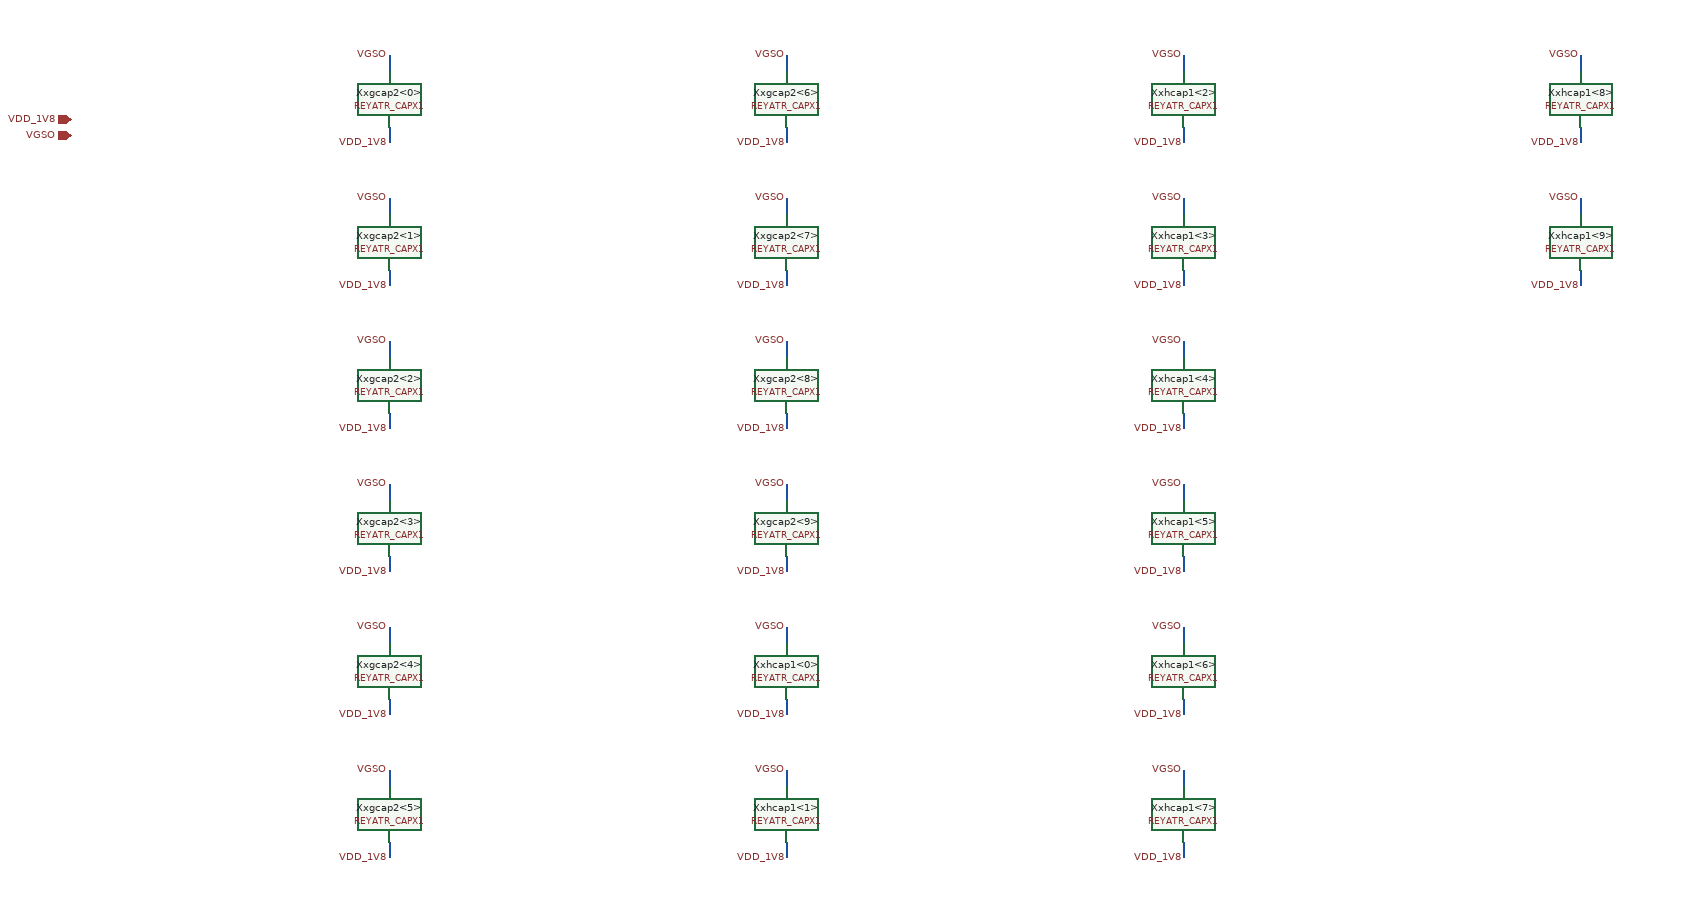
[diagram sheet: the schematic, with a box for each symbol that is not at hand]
v {xschem version=3.0.0 file_version=1.2 }
G {}
K {}
V {}
S {}
E {}
C {devices/iopin.sym} 0 0 0 0 {name=p0 lab=VDD_1V8}
C {devices/iopin.sym} 0 20 0 0 {name=p1 lab=VGSO}
C {REY_ATR_SKY130A/REYATR_CAPX1.sym} 400 0 0 0 {name=Xxgcap2<0>}
N 400.0 -80.0 400.0 -60.0 {lab=VGSO}
C {devices/lab_pin.sym} 400.0 -80.0 3 0 {name=l0 sig_type=std_logic lab=VGSO }
N 400.0 30.0 400.0 10.0 {lab=VDD_1V8}
C {devices/lab_pin.sym} 400.0 30.0 1 0 {name=l1 sig_type=std_logic lab=VDD_1V8 }
C {REY_ATR_SKY130A/REYATR_CAPX1.sym} 400 180.0 0 0 {name=Xxgcap2<1>}
N 400.0 100.0 400.0 120.0 {lab=VGSO}
C {devices/lab_pin.sym} 400.0 100.0 3 0 {name=l2 sig_type=std_logic lab=VGSO }
N 400.0 210.0 400.0 190.0 {lab=VDD_1V8}
C {devices/lab_pin.sym} 400.0 210.0 1 0 {name=l3 sig_type=std_logic lab=VDD_1V8 }
C {REY_ATR_SKY130A/REYATR_CAPX1.sym} 400 360.0 0 0 {name=Xxgcap2<2>}
N 400.0 280.0 400.0 300.0 {lab=VGSO}
C {devices/lab_pin.sym} 400.0 280.0 3 0 {name=l4 sig_type=std_logic lab=VGSO }
N 400.0 390.0 400.0 370.0 {lab=VDD_1V8}
C {devices/lab_pin.sym} 400.0 390.0 1 0 {name=l5 sig_type=std_logic lab=VDD_1V8 }
C {REY_ATR_SKY130A/REYATR_CAPX1.sym} 400 540.0 0 0 {name=Xxgcap2<3>}
N 400.0 460.0 400.0 480.0 {lab=VGSO}
C {devices/lab_pin.sym} 400.0 460.0 3 0 {name=l6 sig_type=std_logic lab=VGSO }
N 400.0 570.0 400.0 550.0 {lab=VDD_1V8}
C {devices/lab_pin.sym} 400.0 570.0 1 0 {name=l7 sig_type=std_logic lab=VDD_1V8 }
C {REY_ATR_SKY130A/REYATR_CAPX1.sym} 400 720.0 0 0 {name=Xxgcap2<4>}
N 400.0 640.0 400.0 660.0 {lab=VGSO}
C {devices/lab_pin.sym} 400.0 640.0 3 0 {name=l8 sig_type=std_logic lab=VGSO }
N 400.0 750.0 400.0 730.0 {lab=VDD_1V8}
C {devices/lab_pin.sym} 400.0 750.0 1 0 {name=l9 sig_type=std_logic lab=VDD_1V8 }
C {REY_ATR_SKY130A/REYATR_CAPX1.sym} 400 900.0 0 0 {name=Xxgcap2<5>}
N 400.0 820.0 400.0 840.0 {lab=VGSO}
C {devices/lab_pin.sym} 400.0 820.0 3 0 {name=l10 sig_type=std_logic lab=VGSO }
N 400.0 930.0 400.0 910.0 {lab=VDD_1V8}
C {devices/lab_pin.sym} 400.0 930.0 1 0 {name=l11 sig_type=std_logic lab=VDD_1V8 }
C {REY_ATR_SKY130A/REYATR_CAPX1.sym} 900 0 0 0 {name=Xxgcap2<6>}
N 900.0 -80.0 900.0 -60.0 {lab=VGSO}
C {devices/lab_pin.sym} 900.0 -80.0 3 0 {name=l12 sig_type=std_logic lab=VGSO }
N 900.0 30.0 900.0 10.0 {lab=VDD_1V8}
C {devices/lab_pin.sym} 900.0 30.0 1 0 {name=l13 sig_type=std_logic lab=VDD_1V8 }
C {REY_ATR_SKY130A/REYATR_CAPX1.sym} 900 180.0 0 0 {name=Xxgcap2<7>}
N 900.0 100.0 900.0 120.0 {lab=VGSO}
C {devices/lab_pin.sym} 900.0 100.0 3 0 {name=l14 sig_type=std_logic lab=VGSO }
N 900.0 210.0 900.0 190.0 {lab=VDD_1V8}
C {devices/lab_pin.sym} 900.0 210.0 1 0 {name=l15 sig_type=std_logic lab=VDD_1V8 }
C {REY_ATR_SKY130A/REYATR_CAPX1.sym} 900 360.0 0 0 {name=Xxgcap2<8>}
N 900.0 280.0 900.0 300.0 {lab=VGSO}
C {devices/lab_pin.sym} 900.0 280.0 3 0 {name=l16 sig_type=std_logic lab=VGSO }
N 900.0 390.0 900.0 370.0 {lab=VDD_1V8}
C {devices/lab_pin.sym} 900.0 390.0 1 0 {name=l17 sig_type=std_logic lab=VDD_1V8 }
C {REY_ATR_SKY130A/REYATR_CAPX1.sym} 900 540.0 0 0 {name=Xxgcap2<9>}
N 900.0 460.0 900.0 480.0 {lab=VGSO}
C {devices/lab_pin.sym} 900.0 460.0 3 0 {name=l18 sig_type=std_logic lab=VGSO }
N 900.0 570.0 900.0 550.0 {lab=VDD_1V8}
C {devices/lab_pin.sym} 900.0 570.0 1 0 {name=l19 sig_type=std_logic lab=VDD_1V8 }
C {REY_ATR_SKY130A/REYATR_CAPX1.sym} 900 720.0 0 0 {name=Xxhcap1<0>}
N 900.0 640.0 900.0 660.0 {lab=VGSO}
C {devices/lab_pin.sym} 900.0 640.0 3 0 {name=l20 sig_type=std_logic lab=VGSO }
N 900.0 750.0 900.0 730.0 {lab=VDD_1V8}
C {devices/lab_pin.sym} 900.0 750.0 1 0 {name=l21 sig_type=std_logic lab=VDD_1V8 }
C {REY_ATR_SKY130A/REYATR_CAPX1.sym} 900 900.0 0 0 {name=Xxhcap1<1>}
N 900.0 820.0 900.0 840.0 {lab=VGSO}
C {devices/lab_pin.sym} 900.0 820.0 3 0 {name=l22 sig_type=std_logic lab=VGSO }
N 900.0 930.0 900.0 910.0 {lab=VDD_1V8}
C {devices/lab_pin.sym} 900.0 930.0 1 0 {name=l23 sig_type=std_logic lab=VDD_1V8 }
C {REY_ATR_SKY130A/REYATR_CAPX1.sym} 1400 0 0 0 {name=Xxhcap1<2>}
N 1400.0 -80.0 1400.0 -60.0 {lab=VGSO}
C {devices/lab_pin.sym} 1400.0 -80.0 3 0 {name=l24 sig_type=std_logic lab=VGSO }
N 1400.0 30.0 1400.0 10.0 {lab=VDD_1V8}
C {devices/lab_pin.sym} 1400.0 30.0 1 0 {name=l25 sig_type=std_logic lab=VDD_1V8 }
C {REY_ATR_SKY130A/REYATR_CAPX1.sym} 1400 180.0 0 0 {name=Xxhcap1<3>}
N 1400.0 100.0 1400.0 120.0 {lab=VGSO}
C {devices/lab_pin.sym} 1400.0 100.0 3 0 {name=l26 sig_type=std_logic lab=VGSO }
N 1400.0 210.0 1400.0 190.0 {lab=VDD_1V8}
C {devices/lab_pin.sym} 1400.0 210.0 1 0 {name=l27 sig_type=std_logic lab=VDD_1V8 }
C {REY_ATR_SKY130A/REYATR_CAPX1.sym} 1400 360.0 0 0 {name=Xxhcap1<4>}
N 1400.0 280.0 1400.0 300.0 {lab=VGSO}
C {devices/lab_pin.sym} 1400.0 280.0 3 0 {name=l28 sig_type=std_logic lab=VGSO }
N 1400.0 390.0 1400.0 370.0 {lab=VDD_1V8}
C {devices/lab_pin.sym} 1400.0 390.0 1 0 {name=l29 sig_type=std_logic lab=VDD_1V8 }
C {REY_ATR_SKY130A/REYATR_CAPX1.sym} 1400 540.0 0 0 {name=Xxhcap1<5>}
N 1400.0 460.0 1400.0 480.0 {lab=VGSO}
C {devices/lab_pin.sym} 1400.0 460.0 3 0 {name=l30 sig_type=std_logic lab=VGSO }
N 1400.0 570.0 1400.0 550.0 {lab=VDD_1V8}
C {devices/lab_pin.sym} 1400.0 570.0 1 0 {name=l31 sig_type=std_logic lab=VDD_1V8 }
C {REY_ATR_SKY130A/REYATR_CAPX1.sym} 1400 720.0 0 0 {name=Xxhcap1<6>}
N 1400.0 640.0 1400.0 660.0 {lab=VGSO}
C {devices/lab_pin.sym} 1400.0 640.0 3 0 {name=l32 sig_type=std_logic lab=VGSO }
N 1400.0 750.0 1400.0 730.0 {lab=VDD_1V8}
C {devices/lab_pin.sym} 1400.0 750.0 1 0 {name=l33 sig_type=std_logic lab=VDD_1V8 }
C {REY_ATR_SKY130A/REYATR_CAPX1.sym} 1400 900.0 0 0 {name=Xxhcap1<7>}
N 1400.0 820.0 1400.0 840.0 {lab=VGSO}
C {devices/lab_pin.sym} 1400.0 820.0 3 0 {name=l34 sig_type=std_logic lab=VGSO }
N 1400.0 930.0 1400.0 910.0 {lab=VDD_1V8}
C {devices/lab_pin.sym} 1400.0 930.0 1 0 {name=l35 sig_type=std_logic lab=VDD_1V8 }
C {REY_ATR_SKY130A/REYATR_CAPX1.sym} 1900 0 0 0 {name=Xxhcap1<8>}
N 1900.0 -80.0 1900.0 -60.0 {lab=VGSO}
C {devices/lab_pin.sym} 1900.0 -80.0 3 0 {name=l36 sig_type=std_logic lab=VGSO }
N 1900.0 30.0 1900.0 10.0 {lab=VDD_1V8}
C {devices/lab_pin.sym} 1900.0 30.0 1 0 {name=l37 sig_type=std_logic lab=VDD_1V8 }
C {REY_ATR_SKY130A/REYATR_CAPX1.sym} 1900 180.0 0 0 {name=Xxhcap1<9>}
N 1900.0 100.0 1900.0 120.0 {lab=VGSO}
C {devices/lab_pin.sym} 1900.0 100.0 3 0 {name=l38 sig_type=std_logic lab=VGSO }
N 1900.0 210.0 1900.0 190.0 {lab=VDD_1V8}
C {devices/lab_pin.sym} 1900.0 210.0 1 0 {name=l39 sig_type=std_logic lab=VDD_1V8 }
